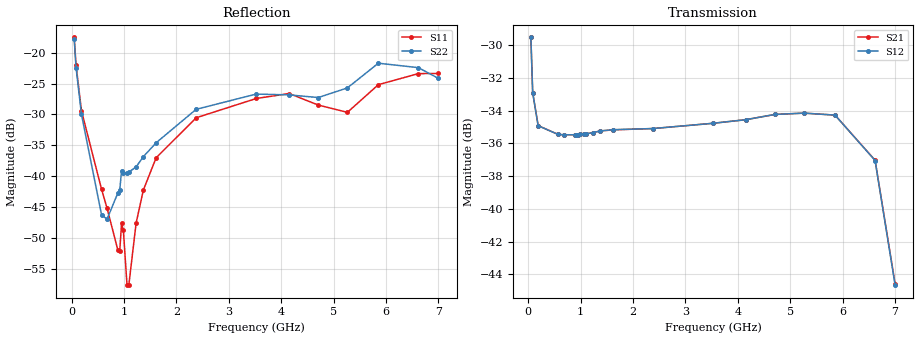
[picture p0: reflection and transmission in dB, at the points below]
! Integrated Device Technology
! Corporate Headquarters
! 6024 Silver Creek Valley Road
! San Jose, CA 95138  USA
! Phone:  1-408-284-8200
! Toll Free:  1-800-223-1366
! Webpage:  http://www.idt.com/
! Timing and RF Division
! 515 Groton Road, Suite 102
! Westford, MA 01886-6024
! Device:  F2258
! Description: Voltage Variable RF Attenuator
! Frequency:  50.0 -  6000.00 MHz
! Package:  3x3 mm Thin QFN Plastic Package: 16 pin
! Ports:  2 RF, 2 DC
!  Pin  1  = NC
!  Pin  2  = NC
!  Pin  3  = RF2  = Port 2
!  Pin  4  = GND
!  Pin  5  = Vdd
!  Pin  6  = NC
!  Pin  7  = VCTRL
!  Pin  8  = NC
!  Pin  9  = GND
!  Pin 10  = RF1  = Port 1
!  Pin 11  = NC
!  Pin 12  = NC
!  Pin 13  = NC
!  Pin 14  = NC
!  Pin 15  = NC
!  Pin 16  = NC
! Vcntrl:  2.370 Volts
! Vdd:  +3.300 Volts
! Current:  1.148 mA
! Data:  The device was measured on a the F2258 evaluation board which has
!  individual transmission lines to the RF pins.  Data was collected
!  using a calibrated network analyzer.  The evaluation board was
!  de-embedded using a TRL calibration technique.
!  The reference plane is the edge of the package pin.
! Misc:  SN 10
!  Action Tracker AT0285
! Date Measured:  2014-12-10
! Date:  2016-01-13  MJV
! Note:
!  Integrated Device Technology supplies this data as a sample of measured
!  data at the package pin for this product.  Your particular data for this
!  product may vary.
!  Data was taken at 25 degrees C.
!  Integrated Device Technology reserves the right to change this data at anytime.
!Freq_(GHz)  S11M_(dB)  S11P_(deg)  S21M_(dB)  S21P_(deg)  S12M_(dB)  S12P_(deg)  S22M_(dB)  S22P_(deg)
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# GHz S dB R 50
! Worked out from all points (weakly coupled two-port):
!   201 points, 50 MHz to 7 GHz, reference 50 ohm
!   highest |S21| = -29.54 dB at 50 MHz (marker M1); lowest = -44.6 dB at 7 GHz (marker M2)
!   lowest |S11| = -57.6 dB at 1.058 GHz (marker M3), VSWR 1.00, Z = 49.9 + j0.0566 ohm
!   |S11| at or under -10 dB: start of sweep to end of sweep
!   |S22| runs from -46.9 to -17.8 dB; largest |S21 - S12| = 7.9e-05
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0.05  -17.55 -111.0  -29.54 -68.6  -29.54 -68.6  -17.78 -111.6
0.08475  -21.98 -107.5  -32.91 -48.9  -32.91 -48.9  -22.42 -108.2
0.189  -29.42 -109.5  -34.92 -24.8  -34.93 -24.8  -30.00 -111.8
0.57125  -42.07 -124.9  -35.46 -10.4  -35.46 -10.4  -46.18 -169.9
0.6755  -45.10 -132.1  -35.48 -9.5  -35.48 -9.4  -46.93 152.6
0.884  -51.94 166.2  -35.48 -8.4  -35.48 -8.4  -42.67 125.1
0.91875  -52.09 150.3  -35.47 -8.3  -35.47 -8.3  -42.27 123.0
0.9535  -47.61 -162.9  -35.48 -8.2  -35.48 -8.2  -39.06 126.5
0.98825  -48.73 -174.4  -35.46 -8.1  -35.46 -8.1  -39.40 124.6
1.05775  -57.57 154.6  -35.44 -7.9  -35.44 -7.9  -39.43 110.9
1.0925  -57.54 121.4  -35.43 -7.8  -35.43 -7.9  -39.32 107.0
1.2315  -47.53 46.6  -35.35 -7.9  -35.35 -7.8  -38.47 85.4
1.3705  -42.18 36.8  -35.25 -8.3  -35.25 -8.3  -36.81 71.7
1.61375  -36.99 32.8  -35.18 -9.5  -35.17 -9.5  -34.57 57.0
2.37825  -30.53 48.2  -35.10 -13.1  -35.10 -13.1  -29.16 45.4
3.525  -27.42 91.7  -34.78 -19.5  -34.78 -19.5  -26.71 68.7
4.1505  -26.62 105.0  -34.56 -23.9  -34.56 -23.9  -26.84 76.2
4.7065  -28.48 95.7  -34.24 -28.6  -34.24 -28.6  -27.27 59.9
5.2625  -29.66 54.3  -34.16 -34.8  -34.16 -34.7  -25.71 22.6
5.85325  -25.19 29.8  -34.28 -45.3  -34.28 -45.4  -21.72 -1.7
6.61775  -23.40 49.7  -37.03 -68.6  -37.05 -68.6  -22.44 -43.6
7  -23.38 84.5  -44.57 -61.5  -44.65 -60.9  -24.18 -130.1
